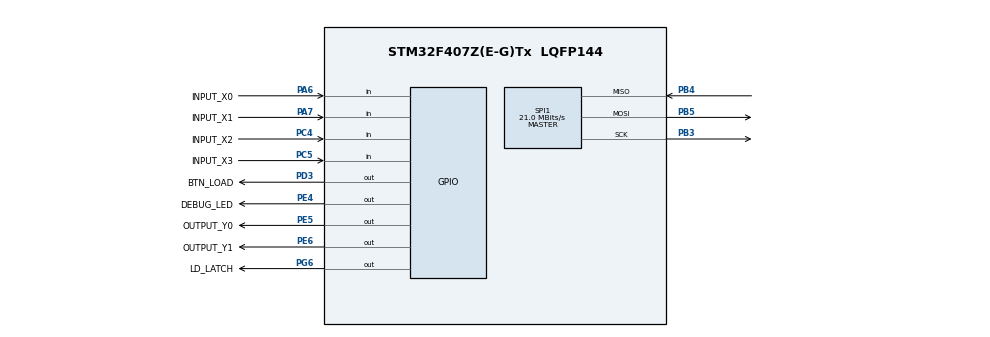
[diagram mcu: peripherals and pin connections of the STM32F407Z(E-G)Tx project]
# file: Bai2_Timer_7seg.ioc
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Mcu.Family=STM32F4
Mcu.Name=STM32F407Z(E-G)Tx
Mcu.Package=LQFP144
NVIC.PriorityGroup=NVIC_PRIORITYGROUP_4
NVIC.TIM2_IRQn=true\:0\:0\:false\:false\:true\:true\:true
PA13.Mode=Serial_Wire
PA13.Signal=SYS_JTMS-SWDIO
PA14.Mode=Serial_Wire
PA14.Signal=SYS_JTCK-SWCLK
PA6.GPIO_Label=INPUT_X0
PA6.Signal=GPIO_Input
PA7.GPIO_Label=INPUT_X1
PA7.Signal=GPIO_Input
PB3.Mode=Full_Duplex_Master
PB3.Signal=SPI1_SCK
PB4.Mode=Full_Duplex_Master
PB4.Signal=SPI1_MISO
PB5.Mode=Full_Duplex_Master
PB5.Signal=SPI1_MOSI
PC4.GPIO_Label=INPUT_X2
PC4.Signal=GPIO_Input
PC5.GPIO_Label=INPUT_X3
PC5.Signal=GPIO_Input
PD3.GPIO_Label=BTN_LOAD
PD3.Signal=GPIO_Output
PE4.GPIO_Label=DEBUG_LED
PE4.Signal=GPIO_Output
PE5.GPIO_Label=OUTPUT_Y0
PE5.Signal=GPIO_Output
PE6.GPIO_Label=OUTPUT_Y1
PE6.Signal=GPIO_Output
PG6.GPIO_Label=LD_LATCH
PG6.Signal=GPIO_Output
PH0-OSC_IN.Mode=HSE-External-Oscillator
PH0-OSC_IN.Signal=RCC_OSC_IN
PH1-OSC_OUT.Mode=HSE-External-Oscillator
PH1-OSC_OUT.Signal=RCC_OSC_OUT
ProjectManager.HeapSize=0x200
ProjectManager.StackSize=0x400
ProjectManager.TargetToolchain=STM32CubeIDE
RCC.48MHZClocksFreq_Value=84000000
RCC.AHBFreq_Value=168000000
RCC.APB1CLKDivider=RCC_HCLK_DIV4
RCC.APB1Freq_Value=42000000
RCC.APB1TimFreq_Value=84000000
RCC.APB2CLKDivider=RCC_HCLK_DIV4
RCC.APB2Freq_Value=42000000
RCC.APB2TimFreq_Value=84000000
RCC.CortexFreq_Value=168000000
RCC.HCLKFreq_Value=168000000
RCC.HSE_VALUE=8000000
RCC.HSI_VALUE=16000000
RCC.LSE_VALUE=32768
RCC.PLLM=8
RCC.PLLN=168
RCC.SYSCLKFreq_VALUE=168000000
RCC.SYSCLKSource=RCC_SYSCLKSOURCE_PLLCLK
RCC.VCOOutputFreq_Value=336000000
SPI1.CalculateBaudRate=21.0 MBits/s
SPI1.Direction=SPI_DIRECTION_2LINES
SPI1.Mode=SPI_MODE_MASTER
SPI1.VirtualType=VM_MASTER
TIM2.Period=100-1
TIM2.Prescaler=420-1
VP_TIM2_VS_ClockSourceINT.Mode=Internal
board=custom

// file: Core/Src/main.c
/* USER CODE BEGIN Header */
/**
  ******************************************************************************
  * @file           : main.c
  * @brief          : Main program body
  ******************************************************************************
  * @attention
  *
  * <h2><center>&copy; Copyright (c) 2023 STMicroelectronics.
  * All rights reserved.</center></h2>
  *
  * This software component is licensed by ST under BSD 3-Clause license,
  * the "License"; You may not use this file except in compliance with the
  * License. You may obtain a copy of the License at:
  *                        opensource.org/licenses/BSD-3-Clause
  *
  ******************************************************************************
  */
/* USER CODE END Header */
#include "main.h"
#include "spi.h"
#include "tim.h"
#include "gpio.h"

/* USER CODE BEGIN Includes */
#include "software_timer.h"
#include "led_7seg.h"
/* USER CODE END Includes */

void SystemClock_Config(void);
/* USER CODE BEGIN PFP */
void system_init();
void test_LedDebug();
void test_LedY0();
void test_LedY1();
void test_7seg();
/* USER CODE END PFP */

int main(void)
{

  /* MCU Configuration--------------------------------------------------------*/

  /* Reset of all peripherals, Initializes the Flash interface and the Systick. */
  HAL_Init();

  /* Configure the system clock */
  SystemClock_Config();

  /* Initialize all configured peripherals */
  MX_GPIO_Init();
  MX_TIM2_Init();
  MX_SPI1_Init();
  /* USER CODE BEGIN 2 */
  system_init();
  led7_SetColon(1);
  int counter = 0;
  /* USER CODE END 2 */

  /* Infinite loop */
  /* USER CODE BEGIN WHILE */
  while (1)
  {
	 counter = (counter + 1) % 6;
	 if(counter < 2){
		 HAL_GPIO_WritePin(DEBUG_LED_GPIO_Port, DEBUG_LED_Pin, 1);
	 }
	 else{
		 HAL_GPIO_WritePin(DEBUG_LED_GPIO_Port, DEBUG_LED_Pin, 0);
	 }
	 HAL_Delay(1000);
    /* USER CODE END WHILE */

  }
}

void SystemClock_Config(void)
{
  RCC_OscInitTypeDef RCC_OscInitStruct = {0};
  RCC_ClkInitTypeDef RCC_ClkInitStruct = {0};

  /** Configure the main internal regulator output voltage
  */
  __HAL_RCC_PWR_CLK_ENABLE();
  __HAL_PWR_VOLTAGESCALING_CONFIG(PWR_REGULATOR_VOLTAGE_SCALE1);
  /** Initializes the RCC Oscillators according to the specified parameters
  * in the RCC_OscInitTypeDef structure.
  */
  RCC_OscInitStruct.OscillatorType = RCC_OSCILLATORTYPE_HSI;
  RCC_OscInitStruct.HSIState = RCC_HSI_ON;
  RCC_OscInitStruct.HSICalibrationValue = RCC_HSICALIBRATION_DEFAULT;
  RCC_OscInitStruct.PLL.PLLState = RCC_PLL_ON;
  RCC_OscInitStruct.PLL.PLLSource = RCC_PLLSOURCE_HSI;
  RCC_OscInitStruct.PLL.PLLM = 8;
  RCC_OscInitStruct.PLL.PLLN = 168;
  RCC_OscInitStruct.PLL.PLLP = RCC_PLLP_DIV2;
  RCC_OscInitStruct.PLL.PLLQ = 4;
  if (HAL_RCC_OscConfig(&RCC_OscInitStruct) != HAL_OK)
  {
    Error_Handler();
  }
  /** Initializes the CPU, AHB and APB buses clocks
  */
  RCC_ClkInitStruct.ClockType = RCC_CLOCKTYPE_HCLK|RCC_CLOCKTYPE_SYSCLK
                              |RCC_CLOCKTYPE_PCLK1|RCC_CLOCKTYPE_PCLK2;
  RCC_ClkInitStruct.SYSCLKSource = RCC_SYSCLKSOURCE_PLLCLK;
  RCC_ClkInitStruct.AHBCLKDivider = RCC_SYSCLK_DIV1;
  RCC_ClkInitStruct.APB1CLKDivider = RCC_HCLK_DIV4;
  RCC_ClkInitStruct.APB2CLKDivider = RCC_HCLK_DIV2;

  if (HAL_RCC_ClockConfig(&RCC_ClkInitStruct, FLASH_LATENCY_5) != HAL_OK)
  {
    Error_Handler();
  }
}

/* USER CODE BEGIN 4 */
void system_init(){
	  HAL_GPIO_WritePin(OUTPUT_Y0_GPIO_Port, OUTPUT_Y0_Pin, 0);
	  HAL_GPIO_WritePin(OUTPUT_Y1_GPIO_Port, OUTPUT_Y1_Pin, 0);
	  HAL_GPIO_WritePin(DEBUG_LED_GPIO_Port, DEBUG_LED_Pin, 0);
	  timer_init();
	  led7_init();
	  //setTimer2(50);
}

uint8_t count_led_debug = 0;
uint8_t count_led_Y0 = 0;
uint8_t count_led_Y1 = 0;

void test_LedDebug(){
	count_led_debug = (count_led_debug + 1)%20;
	if(count_led_debug == 0){
		HAL_GPIO_TogglePin(DEBUG_LED_GPIO_Port, DEBUG_LED_Pin);
	}
}

void test_LedY0(){
	count_led_Y0 = (count_led_Y0+ 1)%100;
	if(count_led_Y0 > 40){
		HAL_GPIO_WritePin(OUTPUT_Y0_GPIO_Port, OUTPUT_Y0_Pin, 1);
	} else {
		HAL_GPIO_WritePin(OUTPUT_Y0_GPIO_Port, OUTPUT_Y0_Pin, 0);
	}
}

void test_LedY1(){
	count_led_Y1 = (count_led_Y1+ 1)%40;
	if(count_led_Y1 > 10){
		HAL_GPIO_WritePin(OUTPUT_Y1_GPIO_Port, OUTPUT_Y1_Pin, 0);
	} else {
		HAL_GPIO_WritePin(OUTPUT_Y0_GPIO_Port, OUTPUT_Y1_Pin, 1);
	}
}

void test_7seg(){
	//write number1 at led index 0 (not show dot)
	led7_SetDigit(1, 0, 0);
	led7_SetDigit(5, 1, 0);
	led7_SetDigit(4, 2, 0);
	led7_SetDigit(7, 3, 0);
}
/* USER CODE END 4 */

void Error_Handler(void)
{
  __disable_irq();
  while (1)
  {
  }
}

/************************ (C) COPYRIGHT STMicroelectronics *****END OF FILE****/
